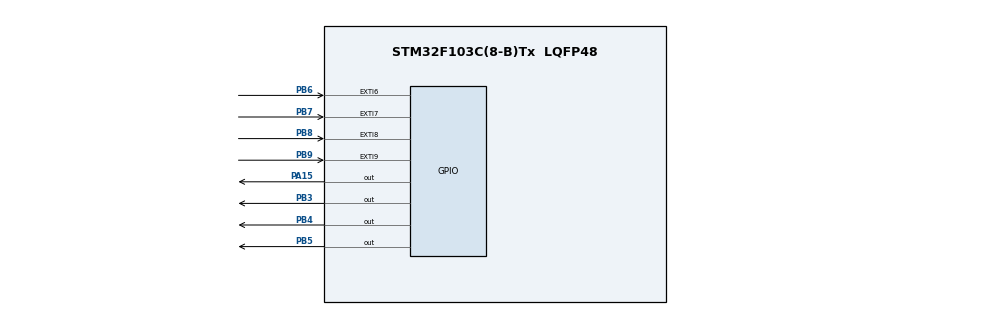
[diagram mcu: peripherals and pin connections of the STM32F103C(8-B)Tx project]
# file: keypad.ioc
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Mcu.Family=STM32F1
Mcu.Name=STM32F103C(8-B)Tx
Mcu.Package=LQFP48
NVIC.EXTI9_5_IRQn=true\:0\:0\:false\:false\:true\:true\:true
NVIC.PriorityGroup=NVIC_PRIORITYGROUP_4
PA13.Mode=Serial_Wire
PA13.Signal=SYS_JTMS-SWDIO
PA14.Mode=Serial_Wire
PA14.Signal=SYS_JTCK-SWCLK
PA15.GPIO_Speed=GPIO_SPEED_FREQ_HIGH
PA15.PinState=GPIO_PIN_SET
PA15.Signal=GPIO_Output
PB3.GPIO_Speed=GPIO_SPEED_FREQ_HIGH
PB3.PinState=GPIO_PIN_SET
PB3.Signal=GPIO_Output
PB4.GPIO_Speed=GPIO_SPEED_FREQ_HIGH
PB4.PinState=GPIO_PIN_SET
PB4.Signal=GPIO_Output
PB5.GPIO_Speed=GPIO_SPEED_FREQ_HIGH
PB5.PinState=GPIO_PIN_SET
PB5.Signal=GPIO_Output
PB6.Signal=GPXTI6
PB7.Signal=GPXTI7
PB8.Signal=GPXTI8
PB9.Signal=GPXTI9
PD0-OSC_IN.Mode=HSE-External-Oscillator
PD0-OSC_IN.Signal=RCC_OSC_IN
PD1-OSC_OUT.Mode=HSE-External-Oscillator
PD1-OSC_OUT.Signal=RCC_OSC_OUT
ProjectManager.HeapSize=0x200
ProjectManager.StackSize=0x400
ProjectManager.TargetToolchain=STM32CubeIDE
RCC.AHBFreq_Value=16000000
RCC.APB1Freq_Value=16000000
RCC.APB1TimFreq_Value=16000000
RCC.APB2Freq_Value=16000000
RCC.APB2TimFreq_Value=16000000
RCC.HCLKFreq_Value=16000000
RCC.PLLSourceVirtual=RCC_PLLSOURCE_HSE
RCC.SYSCLKFreq_VALUE=16000000
RCC.SYSCLKSource=RCC_SYSCLKSOURCE_PLLCLK
RCC.USBFreq_Value=16000000
board=custom

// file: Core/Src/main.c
/* USER CODE BEGIN Header */
/**
  ******************************************************************************
  * @file           : main.c
  * @brief          : Main program body
  ******************************************************************************
  * @attention
  *
  * <h2><center>&copy; Copyright (c) 2021 STMicroelectronics.
  * All rights reserved.</center></h2>
  *
  * This software component is licensed by ST under BSD 3-Clause license,
  * the "License"; You may not use this file except in compliance with the
  * License. You may obtain a copy of the License at:
  *                        opensource.org/licenses/BSD-3-Clause
  *
  ******************************************************************************
  */
/* USER CODE END Header */
#include "main.h"

/* USER CODE BEGIN PV */
GPIO_InitTypeDef GPIO_InitStructPrivate = {0};
uint32_t previousMillis = 0;
uint32_t currentMillis = 0;
uint8_t keyPressed = 0;
/* USER CODE END PV */

void SystemClock_Config(void);
static void MX_GPIO_Init(void);

int main(void)
{

  /* MCU Configuration--------------------------------------------------------*/

  /* Reset of all peripherals, Initializes the Flash interface and the Systick. */
  HAL_Init();

  /* Configure the system clock */
  SystemClock_Config();

  /* Initialize all configured peripherals */
  MX_GPIO_Init();
  /* USER CODE BEGIN 2 */
  HAL_GPIO_WritePin(GPIOA, GPIO_PIN_15, 1);
  HAL_GPIO_WritePin(GPIOB, GPIO_PIN_3, 1);
  HAL_GPIO_WritePin(GPIOB, GPIO_PIN_4, 1);
  HAL_GPIO_WritePin(GPIOB, GPIO_PIN_5, 1);
  /* USER CODE END 2 */

  /* Infinite loop */
  while (1)
  {

  }
}

void SystemClock_Config(void)
{
  RCC_OscInitTypeDef RCC_OscInitStruct = {0};
  RCC_ClkInitTypeDef RCC_ClkInitStruct = {0};

  /** Initializes the RCC Oscillators according to the specified parameters
  * in the RCC_OscInitTypeDef structure.
  */
  RCC_OscInitStruct.OscillatorType = RCC_OSCILLATORTYPE_HSI;
  RCC_OscInitStruct.HSIState = RCC_HSI_ON;
  RCC_OscInitStruct.HSICalibrationValue = RCC_HSICALIBRATION_DEFAULT;
  RCC_OscInitStruct.PLL.PLLState = RCC_PLL_NONE;
  if (HAL_RCC_OscConfig(&RCC_OscInitStruct) != HAL_OK)
  {
    Error_Handler();
  }
  /** Initializes the CPU, AHB and APB buses clocks
  */
  RCC_ClkInitStruct.ClockType = RCC_CLOCKTYPE_HCLK|RCC_CLOCKTYPE_SYSCLK
                              |RCC_CLOCKTYPE_PCLK1|RCC_CLOCKTYPE_PCLK2;
  RCC_ClkInitStruct.SYSCLKSource = RCC_SYSCLKSOURCE_HSI;
  RCC_ClkInitStruct.AHBCLKDivider = RCC_SYSCLK_DIV1;
  RCC_ClkInitStruct.APB1CLKDivider = RCC_HCLK_DIV1;
  RCC_ClkInitStruct.APB2CLKDivider = RCC_HCLK_DIV1;

  if (HAL_RCC_ClockConfig(&RCC_ClkInitStruct, FLASH_LATENCY_0) != HAL_OK)
  {
    Error_Handler();
  }
}

static void MX_GPIO_Init(void)
{
  GPIO_InitTypeDef GPIO_InitStruct = {0};

  /* GPIO Ports Clock Enable */
  __HAL_RCC_GPIOA_CLK_ENABLE();
  __HAL_RCC_GPIOB_CLK_ENABLE();

  /*Configure GPIO pin Output Level */
  HAL_GPIO_WritePin(GPIOA, GPIO_PIN_15, GPIO_PIN_RESET);

  /*Configure GPIO pin Output Level */
  HAL_GPIO_WritePin(GPIOB, GPIO_PIN_3|GPIO_PIN_4|GPIO_PIN_5, GPIO_PIN_RESET);

  /*Configure GPIO pin : PA15 */
  GPIO_InitStruct.Pin = GPIO_PIN_15;
  GPIO_InitStruct.Mode = GPIO_MODE_OUTPUT_PP;
  GPIO_InitStruct.Pull = GPIO_NOPULL;
  GPIO_InitStruct.Speed = GPIO_SPEED_FREQ_LOW;
  HAL_GPIO_Init(GPIOA, &GPIO_InitStruct);

  /*Configure GPIO pins : PB3 PB4 PB5 */
  GPIO_InitStruct.Pin = GPIO_PIN_3|GPIO_PIN_4|GPIO_PIN_5;
  GPIO_InitStruct.Mode = GPIO_MODE_OUTPUT_PP;
  GPIO_InitStruct.Pull = GPIO_NOPULL;
  GPIO_InitStruct.Speed = GPIO_SPEED_FREQ_LOW;
  HAL_GPIO_Init(GPIOB, &GPIO_InitStruct);

  /*Configure GPIO pins : PB6 PB7 PB8 PB9 */
  GPIO_InitStruct.Pin = GPIO_PIN_6|GPIO_PIN_7|GPIO_PIN_8|GPIO_PIN_9;
  GPIO_InitStruct.Mode = GPIO_MODE_IT_RISING;
  GPIO_InitStruct.Pull = GPIO_NOPULL;
  HAL_GPIO_Init(GPIOB, &GPIO_InitStruct);

  /* EXTI interrupt init*/
  HAL_NVIC_SetPriority(EXTI9_5_IRQn, 0, 0);
  HAL_NVIC_EnableIRQ(EXTI9_5_IRQn);

}

/* USER CODE BEGIN 4 */
void HAL_GPIO_EXTI_Callback(uint16_t GPIO_Pin)
{
  currentMillis = HAL_GetTick();
  if (currentMillis - previousMillis > 10) {
    /*Configure GPIO pins : PB6 PB7 PB8 PB9 to GPIO_INPUT*/
    GPIO_InitStructPrivate.Pin = GPIO_PIN_6|GPIO_PIN_7|GPIO_PIN_8|GPIO_PIN_9;
    GPIO_InitStructPrivate.Mode = GPIO_MODE_INPUT;
    GPIO_InitStructPrivate.Pull = GPIO_NOPULL;
    GPIO_InitStructPrivate.Speed = GPIO_SPEED_FREQ_LOW;
    HAL_GPIO_Init(GPIOB, &GPIO_InitStructPrivate);

    HAL_GPIO_WritePin(GPIOA, GPIO_PIN_15, 1);
    HAL_GPIO_WritePin(GPIOB, GPIO_PIN_3, 0);
    HAL_GPIO_WritePin(GPIOB, GPIO_PIN_4, 0);
    HAL_GPIO_WritePin(GPIOB, GPIO_PIN_5, 0);

    if(GPIO_Pin == GPIO_PIN_6 && HAL_GPIO_ReadPin(GPIOB, GPIO_PIN_6))
    {
      keyPressed = 68; //ASCII value of D
    }
    else if(GPIO_Pin == GPIO_PIN_7 && HAL_GPIO_ReadPin(GPIOB, GPIO_PIN_7))
    {
      keyPressed = 67; //ASCII value of C
    }
    else if(GPIO_Pin == GPIO_PIN_8 && HAL_GPIO_ReadPin(GPIOB, GPIO_PIN_8))
    {
      keyPressed = 66; //ASCII value of B
    }
    else if(GPIO_Pin == GPIO_PIN_9 && HAL_GPIO_ReadPin(GPIOB, GPIO_PIN_9))
    {
      keyPressed = 65; //ASCII value of A
    }

    HAL_GPIO_WritePin(GPIOA, GPIO_PIN_15, 0);
    HAL_GPIO_WritePin(GPIOB, GPIO_PIN_3, 1);
    HAL_GPIO_WritePin(GPIOB, GPIO_PIN_4, 0);
    HAL_GPIO_WritePin(GPIOB, GPIO_PIN_5, 0);
    if(GPIO_Pin == GPIO_PIN_6 && HAL_GPIO_ReadPin(GPIOB, GPIO_PIN_6))
    {
      keyPressed = 35; //ASCII value of #
    }
    else if(GPIO_Pin == GPIO_PIN_7 && HAL_GPIO_ReadPin(GPIOB, GPIO_PIN_7))
    {
      keyPressed = 57; //ASCII value of 9
    }
    else if(GPIO_Pin == GPIO_PIN_8 && HAL_GPIO_ReadPin(GPIOB, GPIO_PIN_8))
    {
      keyPressed = 54; //ASCII value of 6
    }
    else if(GPIO_Pin == GPIO_PIN_9 && HAL_GPIO_ReadPin(GPIOB, GPIO_PIN_9))
    {
      keyPressed = 51; //ASCII value of 3
    }

    HAL_GPIO_WritePin(GPIOA, GPIO_PIN_15, 0);
    HAL_GPIO_WritePin(GPIOB, GPIO_PIN_3, 0);
    HAL_GPIO_WritePin(GPIOB, GPIO_PIN_4, 1);
    HAL_GPIO_WritePin(GPIOB, GPIO_PIN_5, 0);
    if(GPIO_Pin == GPIO_PIN_6 && HAL_GPIO_ReadPin(GPIOB, GPIO_PIN_6))
    {
      keyPressed = 48; //ASCII value of 0
    }
    else if(GPIO_Pin == GPIO_PIN_7 && HAL_GPIO_ReadPin(GPIOB, GPIO_PIN_7))
    {
      keyPressed = 56; //ASCII value of 8
    }
    else if(GPIO_Pin == GPIO_PIN_8 && HAL_GPIO_ReadPin(GPIOB, GPIO_PIN_8))
    {
      keyPressed = 53; //ASCII value of 5
    }
    else if(GPIO_Pin == GPIO_PIN_9 && HAL_GPIO_ReadPin(GPIOB, GPIO_PIN_9))
    {
      keyPressed = 50; //ASCII value of 2
    }

    HAL_GPIO_WritePin(GPIOA, GPIO_PIN_15, 0);
    HAL_GPIO_WritePin(GPIOB, GPIO_PIN_3, 0);
    HAL_GPIO_WritePin(GPIOB, GPIO_PIN_4, 0);
    HAL_GPIO_WritePin(GPIOB, GPIO_PIN_5, 1);
    if(GPIO_Pin == GPIO_PIN_6 && HAL_GPIO_ReadPin(GPIOB, GPIO_PIN_6))
    {
      keyPressed = 42; //ASCII value of *
    }
    else if(GPIO_Pin == GPIO_PIN_7 && HAL_GPIO_ReadPin(GPIOB, GPIO_PIN_7))
    {
      keyPressed = 55; //ASCII value of 7
    }
    else if(GPIO_Pin == GPIO_PIN_8 && HAL_GPIO_ReadPin(GPIOB, GPIO_PIN_8))
    {
      keyPressed = 52; //ASCII value of 4
    }
    else if(GPIO_Pin == GPIO_PIN_9 && HAL_GPIO_ReadPin(GPIOB, GPIO_PIN_9))
    {
      keyPressed = 49; //ASCII value of 1
    }

    HAL_GPIO_WritePin(GPIOA, GPIO_PIN_15, 1);
    HAL_GPIO_WritePin(GPIOB, GPIO_PIN_3, 1);
    HAL_GPIO_WritePin(GPIOB, GPIO_PIN_4, 1);
    HAL_GPIO_WritePin(GPIOB, GPIO_PIN_5, 1);
    /*Configure GPIO pins : PB6 PB7 PB8 PB9 back to EXTI*/
    GPIO_InitStructPrivate.Mode = GPIO_MODE_IT_RISING;
    GPIO_InitStructPrivate.Pull = GPIO_PULLDOWN;
    HAL_GPIO_Init(GPIOB, &GPIO_InitStructPrivate);
    previousMillis = currentMillis;
  }
}
/* USER CODE END 4 */

void Error_Handler(void)
{
  __disable_irq();
  while (1)
  {
  }
}

/************************ (C) COPYRIGHT STMicroelectronics *****END OF FILE****/
